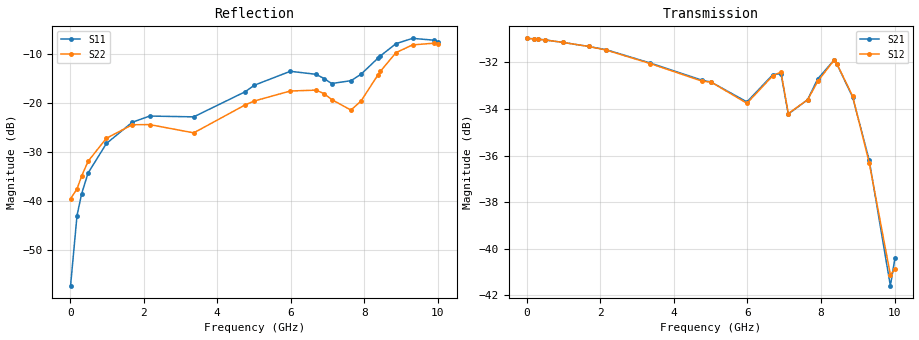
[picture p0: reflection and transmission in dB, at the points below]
! Device ID: PE43705
! Serial: 1
! Insertion: A
! Impedance: 50 ohm
! Temp: 25C
! VDD: 3.400V
! Attenuation Step: 30.00dB
#  Hz  S  RI  R  50
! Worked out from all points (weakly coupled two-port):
!   401 points, 10 MHz to 10.01 GHz, reference 50 ohm
!   highest |S21| = -30.96 dB at 10 MHz (marker M1); lowest = -41.6 dB at 9.885 GHz (marker M2)
!   lowest |S11| = -57.3 dB at 10 MHz (marker M3), VSWR 1.00, Z = 49.9 + j0.0453 ohm
!   |S11| at or under -10 dB: start of sweep to 8.495 GHz
!   |S22| runs from -39.6 to -7.8 dB; largest |S21 - S12| = 0.00067
!   S11 on the Smith chart (normalised r, x): 10 MHz: 1.00, +0.00; 4.76 GHz: 0.80, +0.12; 8.435 GHz: 0.80, +0.53; 9.31 GHz: 0.52, +0.55; 10.01 GHz: 0.47, +0.33
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1e7  -0.00129 0.000454  0.0283 -0.000114  0.0283 -7e-05  -0.0105 0.000561
1.85e8  -0.00176 0.00687  0.0282 -0.00128  0.0282 -0.00129  -0.0101 0.00856
3.1e8  -0.00368 0.0112  0.0281 -0.00211  0.0281 -0.00208  -0.0115 0.0137
4.85e8  -0.00835 0.0173  0.0279 -0.00326  0.0279 -0.00324  -0.0151 0.0203
9.85e8  -0.0309 0.0229  0.027 -0.00634  0.027 -0.00634  -0.0326 0.0288
1.685e9  -0.0624 0.0103  0.0252 -0.0102  0.0252 -0.0102  -0.0552 0.0227
2.16e9  -0.0731 -0.00424  0.0236 -0.0126  0.0236 -0.0125  -0.0585 0.0131
3.36e9  -0.0718 -0.00322  0.0183 -0.0171  0.0183 -0.017  -0.0468 0.0157
4.76e9  -0.1058 0.075  0.013 -0.019  0.0128 -0.019  -0.0783 0.0542
5.01e9  -0.1214 0.09  0.0123 -0.0192  0.0123 -0.0192  -0.0867 0.0581
5.985e9  -0.1753 0.1143  0.00814 -0.019  0.00825 -0.0188  -0.1149 0.0646
6.685e9  -0.1666 0.1016  0.00724 -0.0225  0.00716 -0.0224  -0.1239 0.0524
6.91e9  -0.1473 0.0965  0.00419 -0.0234  0.00415 -0.0236  -0.1135 0.049
7.11e9  -0.1315 0.0861  0.00253 -0.0193  0.00291 -0.0193  -0.0952 0.0506
7.635e9  -0.0823 0.1463  0.00408 -0.0205  0.00404 -0.0205  -0.0501 0.0677
7.91e9  -0.0479 0.1895  0.00349 -0.0229  0.0035 -0.0226  -0.037 0.0975
8.36e9  -0.0225 0.2821  -0.00356 -0.0252  -0.00361 -0.0252  -0.036 0.1867
8.435e9  -0.0247 0.2993  -0.00536 -0.0243  -0.00513 -0.0244  -0.0404 0.2052
8.86e9  -0.0757 0.3932  -0.0099 -0.0187  -0.0101 -0.0187  -0.1038 0.3074
9.31e9  -0.1623 0.4233  -0.00942 -0.0123  -0.00962 -0.0119  -0.2032 0.3315
9.885e9  -0.284 0.3293  -0.002 -0.00809  -0.00221 -0.00852  -0.3439 0.213
1.001e10  -0.2994 0.2891  -0.000215 -0.00953  0.000186 -0.00903  -0.3669 0.1636
